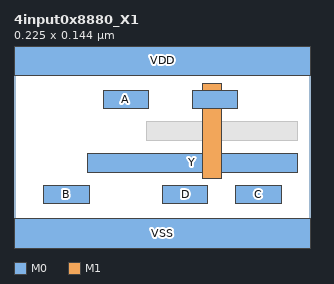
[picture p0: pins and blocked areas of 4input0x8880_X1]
MACRO 4input0x8880_X1
  CLASS CORE ;
  ORIGIN 0 0 ;
  FOREIGN 4input0x8880_X1 0 0 ;
  SIZE 0.2250 BY 0.1440 ;
  SYMMETRY X Y ;
  SITE coresite ;
  PIN A
    DIRECTION INPUT ;
    USE SIGNAL ;
    PORT
      LAYER M0 ;
        RECT 0.0675 0.1010 0.1020 0.1150 ;
    END
  END A
  PIN B
    DIRECTION INPUT ;
    USE SIGNAL ;
    PORT
      LAYER M0 ;
        RECT 0.0225 0.0290 0.0570 0.0430 ;
    END
  END B
  PIN C
    DIRECTION INPUT ;
    USE SIGNAL ;
    PORT
      LAYER M0 ;
        RECT 0.1680 0.0290 0.2025 0.0430 ;
    END
  END C
  PIN D
    DIRECTION INPUT ;
    USE SIGNAL ;
    PORT
      LAYER M0 ;
        RECT 0.1125 0.0290 0.1470 0.0430 ;
    END
  END D
  PIN Y
    DIRECTION OUTPUT ;
    USE SIGNAL ;
    PORT
      LAYER M1 ;
        RECT 0.1425 0.0480 0.1575 0.1200 ;
      LAYER M0 ;
        RECT 0.1350 0.1010 0.1695 0.1150 ;
        RECT 0.0555 0.0530 0.2145 0.0670 ;
    END
  END Y
  PIN VDD
    DIRECTION INOUT ;
    USE POWER ;
    SHAPE ABUTMENT ;
    PORT
      LAYER M0 ;
        RECT 0.0000 0.1260 0.2250 0.1620 ;
    END
  END VDD
  PIN VSS
    DIRECTION INOUT ;
    USE GROUND ;
    SHAPE ABUTMENT ;
    PORT
      LAYER M0 ;
        RECT 0.0000 -0.0180 0.2250 0.0180 ;
    END
  END VSS
  OBS
    LAYER V0 ;
      RECT 0.1430 0.1010 0.1570 0.1150 ;
      RECT 0.1430 0.0530 0.1570 0.0670 ;
    LAYER M0 ;
      RECT 0.1005 0.0770 0.2145 0.0910 ;
  END
END 4input0x8880_X1
